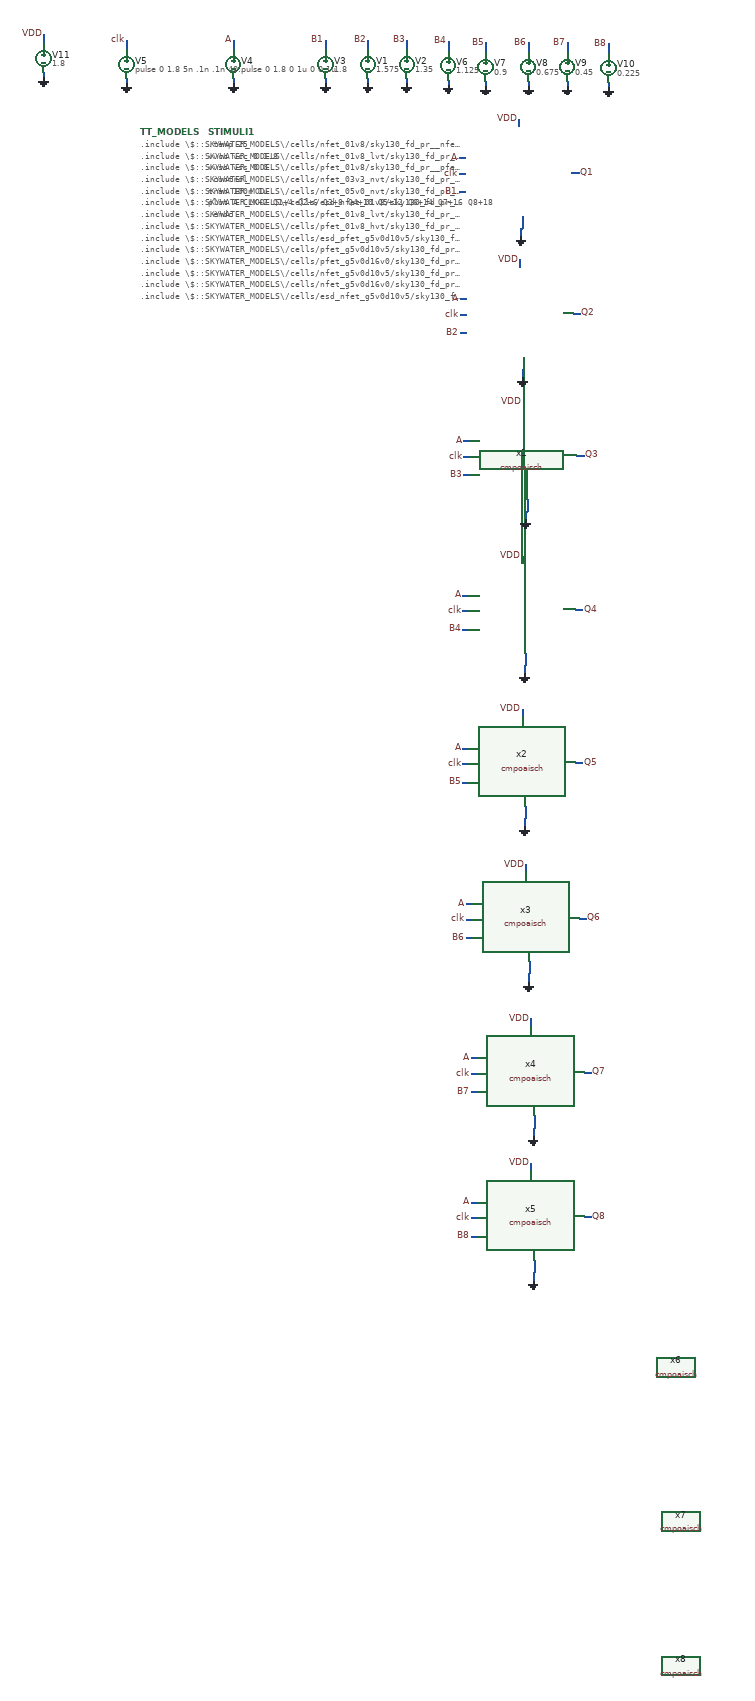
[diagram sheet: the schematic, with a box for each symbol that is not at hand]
v {xschem version=2.9.9 file_version=1.2 }
G {}
K {}
V {}
S {}
E {}
N -132.5 -1525 -132.5 -1520 { lab=GND}
N -132.5 -1542.5 -132.5 -1525 { lab=GND}
N -262.5 -1665 -250 -1665 { lab=A}
N -262.5 -1595 -250 -1595 { lab=B1}
N -132.5 -1545 -132.5 -1542.5 { lab=GND}
N -30 -1635 -15 -1635 { lab=Q1}
N -537.5 -1827.5 -537.5 -1817.5 { lab=GND}
N -727.5 -1827.5 -727.5 -1817.5 { lab=GND}
N -947.5 -1827.5 -947.5 -1817.5 { lab=GND}
N -947.5 -1907.5 -947.5 -1887.5 { lab=clk}
N -727.5 -1907.5 -727.5 -1887.5 { lab=A}
N -537.5 -1907.5 -537.5 -1887.5 { lab=B1}
N -450 -1827.5 -450 -1817.5 { lab=GND}
N -450 -1907.5 -450 -1887.5 { lab=B2}
N -370 -1827.5 -370 -1817.5 { lab=GND}
N -370 -1907.5 -370 -1887.5 { lab=B3}
N -285 -1825 -285 -1815 { lab=GND}
N -285 -1905 -285 -1885 { lab=B4}
N -207.5 -1822.5 -207.5 -1812.5 { lab=GND}
N -207.5 -1902.5 -207.5 -1882.5 { lab=B5}
N -120 -1822.5 -120 -1812.5 { lab=GND}
N -120 -1902.5 -120 -1882.5 { lab=B6}
N -40 -1822.5 -40 -1812.5 { lab=GND}
N -40 -1902.5 -40 -1882.5 { lab=B7}
N 45 -1820 45 -1810 { lab=GND}
N 45 -1900 45 -1880 { lab=B8}
N -1117.5 -1840 -1117.5 -1830 { lab=GND}
N -1117.5 -1920 -1117.5 -1900 { lab=VDD}
N -140 -1745 -140 -1730 { lab=VDD}
N -262.5 -1632.5 -250 -1632.5 { lab=clk}
N -135 -1520 -135 -1502.5 { lab=GND}
N -135 -1520 -132.5 -1520 { lab=GND}
N -130 -1235 -130 -1230 { lab=GND}
N -130 -1252.5 -130 -1235 { lab=GND}
N -260 -1375 -247.5 -1375 { lab=A}
N -260 -1305 -247.5 -1305 { lab=B2}
N -130 -1255 -130 -1252.5 { lab=GND}
N -27.5 -1345 -12.5 -1345 { lab=Q2}
N -137.5 -1455 -137.5 -1440 { lab=VDD}
N -260 -1342.5 -247.5 -1342.5 { lab=clk}
N -132.5 -1230 -132.5 -1212.5 { lab=GND}
N -132.5 -1230 -130 -1230 { lab=GND}
N -122.5 -942.5 -122.5 -937.5 { lab=GND}
N -122.5 -960 -122.5 -942.5 { lab=GND}
N -252.5 -1082.5 -240 -1082.5 { lab=A}
N -252.5 -1012.5 -240 -1012.5 { lab=B3}
N -122.5 -962.5 -122.5 -960 { lab=GND}
N -20 -1052.5 -5 -1052.5 { lab=Q3}
N -130 -1162.5 -130 -1147.5 { lab=VDD}
N -252.5 -1050 -240 -1050 { lab=clk}
N -125 -937.5 -125 -920 { lab=GND}
N -125 -937.5 -122.5 -937.5 { lab=GND}
N -125 -625 -125 -620 { lab=GND}
N -125 -642.5 -125 -625 { lab=GND}
N -255 -765 -242.5 -765 { lab=A}
N -255 -695 -242.5 -695 { lab=B4}
N -125 -645 -125 -642.5 { lab=GND}
N -22.5 -735 -7.5 -735 { lab=Q4}
N -132.5 -845 -132.5 -830 { lab=VDD}
N -255 -732.5 -242.5 -732.5 { lab=clk}
N -127.5 -620 -127.5 -602.5 { lab=GND}
N -127.5 -620 -125 -620 { lab=GND}
N -125 -310 -125 -305 { lab=GND}
N -125 -327.5 -125 -310 { lab=GND}
N -255 -450 -242.5 -450 { lab=A}
N -255 -380 -242.5 -380 { lab=B5}
N -125 -330 -125 -327.5 { lab=GND}
N -22.5 -420 -7.5 -420 { lab=Q5}
N -132.5 -530 -132.5 -515 { lab=VDD}
N -255 -417.5 -242.5 -417.5 { lab=clk}
N -127.5 -305 -127.5 -287.5 { lab=GND}
N -127.5 -305 -125 -305 { lab=GND}
N -117.5 10 -117.5 15 { lab=GND}
N -117.5 -7.5 -117.5 10 { lab=GND}
N -247.5 -130 -235 -130 { lab=A}
N -247.5 -60 -235 -60 { lab=B6}
N -117.5 -10 -117.5 -7.5 { lab=GND}
N -15 -100 0 -100 { lab=Q6}
N -125 -210 -125 -195 { lab=VDD}
N -247.5 -97.5 -235 -97.5 { lab=clk}
N -120 15 -120 32.5 { lab=GND}
N -120 15 -117.5 15 { lab=GND}
N -107.5 327.5 -107.5 332.5 { lab=GND}
N -107.5 310 -107.5 327.5 { lab=GND}
N -237.5 187.5 -225 187.5 { lab=A}
N -237.5 257.5 -225 257.5 { lab=B7}
N -107.5 307.5 -107.5 310 { lab=GND}
N -5 217.5 10 217.5 { lab=Q7}
N -115 107.5 -115 122.5 { lab=VDD}
N -237.5 220 -225 220 { lab=clk}
N -110 332.5 -110 350 { lab=GND}
N -110 332.5 -107.5 332.5 { lab=GND}
N -107.5 625 -107.5 630 { lab=GND}
N -107.5 607.5 -107.5 625 { lab=GND}
N -237.5 485 -225 485 { lab=A}
N -237.5 555 -225 555 { lab=B8}
N -107.5 605 -107.5 607.5 { lab=GND}
N -5 515 10 515 { lab=Q8}
N -115 405 -115 420 { lab=VDD}
N -237.5 517.5 -225 517.5 { lab=clk}
N -110 630 -110 647.5 { lab=GND}
N -110 630 -107.5 630 { lab=GND}
C {devices/vsource.sym} -537.5 -1857.5 0 0 {name=V3 value=1.8}
C {devices/vsource.sym} -727.5 -1857.5 0 0 {name=V4 value="pulse 0 1.8 0 1u 0 0 1u"}
C {devices/gnd.sym} -947.5 -1817.5 0 0 {name=l11 lab=GND}
C {devices/gnd.sym} -727.5 -1817.5 0 0 {name=l12 lab=GND}
C {devices/gnd.sym} -537.5 -1817.5 0 0 {name=l13 lab=GND}
C {devices/lab_pin.sym} -537.5 -1907.5 0 0 {name=l14 sig_type=std_logic lab=B1
}
C {devices/lab_pin.sym} -727.5 -1907.5 0 0 {name=l15 sig_type=std_logic lab=A
}
C {devices/lab_pin.sym} -947.5 -1907.5 0 0 {name=l16 sig_type=std_logic lab=clk}
C {devices/vsource.sym} -947.5 -1857.5 0 0 {name=V5 value="pulse 0 1.8 5n .1n .1n 40n 80n"}
C {devices/code.sym} -777.5 -1717.5 0 0 {name=STIMULI1 
only_toplevel=true
place=end
value="
.temp 25
vvcc vcc 0 1.8
vvss vss 0 0
.control
tran 100n 1u
plot A CLK+2 Q1+4 Q2+6 Q3+8 Q4+10 Q5+12 Q6+14 Q7+16 Q8+18
.endc
"}
C {devices/vsource.sym} -450 -1857.5 0 0 {name=V1 value=1.575}
C {devices/gnd.sym} -450 -1817.5 0 0 {name=l8 lab=GND}
C {devices/lab_pin.sym} -450 -1907.5 0 0 {name=l9 sig_type=std_logic lab=B2
}
C {devices/vsource.sym} -370 -1857.5 0 0 {name=V2 value=1.35}
C {devices/gnd.sym} -370 -1817.5 0 0 {name=l10 lab=GND}
C {devices/lab_pin.sym} -370 -1907.5 0 0 {name=l17 sig_type=std_logic lab=B3
}
C {devices/vsource.sym} -285 -1855 0 0 {name=V6 value=1.125}
C {devices/gnd.sym} -285 -1815 0 0 {name=l18 lab=GND}
C {devices/lab_pin.sym} -285 -1905 0 0 {name=l19 sig_type=std_logic lab=B4
}
C {devices/vsource.sym} -207.5 -1852.5 0 0 {name=V7 value=0.9}
C {devices/gnd.sym} -207.5 -1812.5 0 0 {name=l45 lab=GND}
C {devices/lab_pin.sym} -207.5 -1902.5 0 0 {name=l46 sig_type=std_logic lab=B5
}
C {devices/vsource.sym} -120 -1852.5 0 0 {name=V8 value=0.675}
C {devices/gnd.sym} -120 -1812.5 0 0 {name=l47 lab=GND}
C {devices/lab_pin.sym} -120 -1902.5 0 0 {name=l48 sig_type=std_logic lab=B6
}
C {devices/vsource.sym} -40 -1852.5 0 0 {name=V9 value=0.45}
C {devices/gnd.sym} -40 -1812.5 0 0 {name=l49 lab=GND}
C {devices/lab_pin.sym} -40 -1902.5 0 0 {name=l50 sig_type=std_logic lab=B7
}
C {devices/vsource.sym} 45 -1850 0 0 {name=V10 value=0.225}
C {devices/gnd.sym} 45 -1810 0 0 {name=l51 lab=GND}
C {devices/lab_pin.sym} 45 -1900 0 0 {name=l52 sig_type=std_logic lab=B8
}
C {devices/code.sym} -917.5 -1717.5 0 0 {name=TT_MODELS
only_toplevel=true
format="tcleval( @value )"
value="
.include \\\\$::SKYWATER_MODELS\\\\/cells/nfet_01v8/sky130_fd_pr__nfet_01v8__tt.corner.spice
.include \\\\$::SKYWATER_MODELS\\\\/cells/nfet_01v8_lvt/sky130_fd_pr__nfet_01v8_lvt__tt.corner.spice
.include \\\\$::SKYWATER_MODELS\\\\/cells/pfet_01v8/sky130_fd_pr__pfet_01v8__tt.corner.spice
.include \\\\$::SKYWATER_MODELS\\\\/cells/nfet_03v3_nvt/sky130_fd_pr__nfet_03v3_nvt__tt.corner.spice
.include \\\\$::SKYWATER_MODELS\\\\/cells/nfet_05v0_nvt/sky130_fd_pr__nfet_05v0_nvt__tt.corner.spice
.include \\\\$::SKYWATER_MODELS\\\\/cells/esd_nfet_01v8/sky130_fd_pr__esd_nfet_01v8__tt.corner.spice
.include \\\\$::SKYWATER_MODELS\\\\/cells/pfet_01v8_lvt/sky130_fd_pr__pfet_01v8_lvt__tt.corner.spice
.include \\\\$::SKYWATER_MODELS\\\\/cells/pfet_01v8_hvt/sky130_fd_pr__pfet_01v8_hvt__tt.corner.spice
.include \\\\$::SKYWATER_MODELS\\\\/cells/esd_pfet_g5v0d10v5/sky130_fd_pr__esd_pfet_g5v0d10v5__tt.corner.spice
.include \\\\$::SKYWATER_MODELS\\\\/cells/pfet_g5v0d10v5/sky130_fd_pr__pfet_g5v0d10v5__tt.corner.spice
.include \\\\$::SKYWATER_MODELS\\\\/cells/pfet_g5v0d16v0/sky130_fd_pr__pfet_g5v0d16v0__tt.corner.spice
.include \\\\$::SKYWATER_MODELS\\\\/cells/nfet_g5v0d10v5/sky130_fd_pr__nfet_g5v0d10v5__tt.corner.spice
.include \\\\$::SKYWATER_MODELS\\\\/cells/nfet_g5v0d16v0/sky130_fd_pr__nfet_g5v0d16v0__tt_discrete.corner.spice
.include \\\\$::SKYWATER_MODELS\\\\/cells/esd_nfet_g5v0d10v5/sky130_fd_pr__esd_nfet_g5v0d10v5__tt.corner.spice
.include \\\\$::SKYWATER_MODELS\\\\/models/corners/tt/nonfet.spice
* Mismatch parameters
.include \\\\$::SKYWATER_MODELS\\\\/cells/nfet_01v8/sky130_fd_pr__nfet_01v8__mismatch.corner.spice
.include \\\\$::SKYWATER_MODELS\\\\/cells/pfet_01v8/sky130_fd_pr__pfet_01v8__mismatch.corner.spice
.include \\\\$::SKYWATER_MODELS\\\\/cells/nfet_01v8_lvt/sky130_fd_pr__nfet_01v8_lvt__mismatch.corner.spice
.include \\\\$::SKYWATER_MODELS\\\\/cells/pfet_01v8_lvt/sky130_fd_pr__pfet_01v8_lvt__mismatch.corner.spice
.include \\\\$::SKYWATER_MODELS\\\\/cells/pfet_01v8_hvt/sky130_fd_pr__pfet_01v8_hvt__mismatch.corner.spice
.include \\\\$::SKYWATER_MODELS\\\\/cells/nfet_g5v0d10v5/sky130_fd_pr__nfet_g5v0d10v5__mismatch.corner.spice
.include \\\\$::SKYWATER_MODELS\\\\/cells/pfet_g5v0d10v5/sky130_fd_pr__pfet_g5v0d10v5__mismatch.corner.spice
.include \\\\$::SKYWATER_MODELS\\\\/cells/nfet_05v0_nvt/sky130_fd_pr__nfet_05v0_nvt__mismatch.corner.spice
.include \\\\$::SKYWATER_MODELS\\\\/cells/nfet_03v3_nvt/sky130_fd_pr__nfet_03v3_nvt__mismatch.corner.spice
* Resistor\\\\$::SKYWATER_MODELS\\\\/Capacitor
.include \\\\$::SKYWATER_MODELS\\\\/models/r+c/res_typical__cap_typical.spice
.include \\\\$::SKYWATER_MODELS\\\\/models/r+c/res_typical__cap_typical__lin.spice
* Special cells
.include \\\\$::SKYWATER_MODELS\\\\/models/corners/tt/specialized_cells.spice
* All models
.include \\\\$::SKYWATER_MODELS\\\\/models/all.spice
* Corner
.include \\\\$::SKYWATER_MODELS\\\\/models/corners/tt/rf.spice
.include ~/skywater-pdk/libraries/sky130_fd_sc_hd/latest/cells/nand3/sky130_fd_sc_hd__nand3_1.spice
.include ~/skywater-pdk/libraries/sky130_fd_sc_hd/latest/cells/nand2/sky130_fd_sc_hd__nand2_1.spice
.include ~/skywater-pdk/libraries/sky130_fd_sc_hd/latest/cells/nor3/sky130_fd_sc_hd__nor3_1.spice
.include ~/skywater-pdk/libraries/sky130_fd_sc_hd/latest/cells/dfrtp/sky130_fd_sc_hd__dfrtp_1.spice
.include ~/skywater-pdk/libraries/sky130_fd_sc_hd/latest/cells/nor2/sky130_fd_sc_hd__nor2_1.spice
.include ~/skywater-pdk/libraries/sky130_fd_sc_hd/latest/cells/dlrbn/sky130_fd_sc_hd__dlrbn_1.spice
.include ~/skywater-pdk/libraries/sky130_fd_sc_hd/latest/cells/a31o/sky130_fd_sc_hd__a31o_2.spice
.include ~/skywater-pdk/libraries/sky130_fd_sc_hd/latest/cells/inv/sky130_fd_sc_hd__inv_1.spice
.include ~/skywater-pdk/libraries/sky130_fd_sc_hd/latest/cells/a222oi/sky130_fd_sc_hd__a222oi_1.spice
.include ~/skywater-pdk/libraries/sky130_fd_sc_hd/latest/cells/or2/sky130_fd_sc_hd__or2_1.spice
.include ~/skywater-pdk/libraries/sky130_fd_sc_hd/latest/cells/o221ai/sky130_fd_sc_hd__o221ai_1.spice

"}
C {devices/vsource.sym} -1117.5 -1870 0 0 {name=V11 value=1.8}
C {devices/gnd.sym} -1117.5 -1830 0 0 {name=l53 lab=GND}
C {devices/lab_pin.sym} -1117.5 -1920 0 0 {name=l54 sig_type=std_logic lab=VDD
}
C {cmpoaisch.sym} 170 -710 0 0 {name=x1}
C {devices/lab_pin.sym} -262.5 -1665 0 0 {name=l1 sig_type=std_logic lab=A
}
C {devices/lab_pin.sym} -262.5 -1595 0 0 {name=l2 sig_type=std_logic lab=B1
}
C {devices/lab_pin.sym} -262.5 -1632.5 0 0 {name=l3 sig_type=std_logic lab=clk}
C {devices/lab_pin.sym} -140 -1745 0 0 {name=l4 sig_type=std_logic lab=VDD
}
C {devices/gnd.sym} -135 -1502.5 0 0 {name=l5 lab=GND}
C {devices/lab_pin.sym} -15 -1635 2 0 {name=l6 sig_type=std_logic lab=Q1
}
C {cmpoaisch.sym} 172.5 -420 0 0 {name=x2}
C {devices/lab_pin.sym} -260 -1375 0 0 {name=l7 sig_type=std_logic lab=A
}
C {devices/lab_pin.sym} -260 -1305 0 0 {name=l20 sig_type=std_logic lab=B2
}
C {devices/lab_pin.sym} -260 -1342.5 0 0 {name=l21 sig_type=std_logic lab=clk}
C {devices/lab_pin.sym} -137.5 -1455 0 0 {name=l22 sig_type=std_logic lab=VDD
}
C {devices/gnd.sym} -132.5 -1212.5 0 0 {name=l23 lab=GND}
C {devices/lab_pin.sym} -12.5 -1345 2 0 {name=l24 sig_type=std_logic lab=Q2}
C {cmpoaisch.sym} 180 -127.5 0 0 {name=x3}
C {devices/lab_pin.sym} -252.5 -1082.5 0 0 {name=l25 sig_type=std_logic lab=A
}
C {devices/lab_pin.sym} -252.5 -1012.5 0 0 {name=l26 sig_type=std_logic lab=B3
}
C {devices/lab_pin.sym} -252.5 -1050 0 0 {name=l27 sig_type=std_logic lab=clk}
C {devices/lab_pin.sym} -130 -1162.5 0 0 {name=l28 sig_type=std_logic lab=VDD
}
C {devices/gnd.sym} -125 -920 0 0 {name=l29 lab=GND}
C {devices/lab_pin.sym} -5 -1052.5 2 0 {name=l30 sig_type=std_logic lab=Q3
}
C {cmpoaisch.sym} 177.5 190 0 0 {name=x4}
C {devices/lab_pin.sym} -255 -765 0 0 {name=l31 sig_type=std_logic lab=A
}
C {devices/lab_pin.sym} -255 -695 0 0 {name=l32 sig_type=std_logic lab=B4
}
C {devices/lab_pin.sym} -255 -732.5 0 0 {name=l33 sig_type=std_logic lab=clk}
C {devices/lab_pin.sym} -132.5 -845 0 0 {name=l34 sig_type=std_logic lab=VDD
}
C {devices/gnd.sym} -127.5 -602.5 0 0 {name=l35 lab=GND}
C {devices/lab_pin.sym} -7.5 -735 2 0 {name=l36 sig_type=std_logic lab=Q4
}
C {cmpoaisch.sym} 177.5 505 0 0 {name=x5}
C {devices/lab_pin.sym} -255 -450 0 0 {name=l37 sig_type=std_logic lab=A
}
C {devices/lab_pin.sym} -255 -380 0 0 {name=l38 sig_type=std_logic lab=B5
}
C {devices/lab_pin.sym} -255 -417.5 0 0 {name=l39 sig_type=std_logic lab=clk}
C {devices/lab_pin.sym} -132.5 -530 0 0 {name=l40 sig_type=std_logic lab=VDD
}
C {devices/gnd.sym} -127.5 -287.5 0 0 {name=l41 lab=GND}
C {devices/lab_pin.sym} -7.5 -420 2 0 {name=l42 sig_type=std_logic lab=Q5
}
C {cmpoaisch.sym} 185 825 0 0 {name=x6}
C {devices/lab_pin.sym} -247.5 -130 0 0 {name=l43 sig_type=std_logic lab=A
}
C {devices/lab_pin.sym} -247.5 -60 0 0 {name=l44 sig_type=std_logic lab=B6
}
C {devices/lab_pin.sym} -247.5 -97.5 0 0 {name=l55 sig_type=std_logic lab=clk}
C {devices/lab_pin.sym} -125 -210 0 0 {name=l56 sig_type=std_logic lab=VDD
}
C {devices/gnd.sym} -120 32.5 0 0 {name=l57 lab=GND}
C {devices/lab_pin.sym} 0 -100 2 0 {name=l58 sig_type=std_logic lab=Q6
}
C {cmpoaisch.sym} 195 1142.5 0 0 {name=x7}
C {devices/lab_pin.sym} -237.5 187.5 0 0 {name=l59 sig_type=std_logic lab=A
}
C {devices/lab_pin.sym} -237.5 257.5 0 0 {name=l60 sig_type=std_logic lab=B7
}
C {devices/lab_pin.sym} -237.5 220 0 0 {name=l61 sig_type=std_logic lab=clk}
C {devices/lab_pin.sym} -115 107.5 0 0 {name=l62 sig_type=std_logic lab=VDD
}
C {devices/gnd.sym} -110 350 0 0 {name=l63 lab=GND}
C {devices/lab_pin.sym} 10 217.5 2 0 {name=l64 sig_type=std_logic lab=Q7
}
C {cmpoaisch.sym} 195 1440 0 0 {name=x8}
C {devices/lab_pin.sym} -237.5 485 0 0 {name=l65 sig_type=std_logic lab=A
}
C {devices/lab_pin.sym} -237.5 555 0 0 {name=l66 sig_type=std_logic lab=B8
}
C {devices/lab_pin.sym} -237.5 517.5 0 0 {name=l67 sig_type=std_logic lab=clk}
C {devices/lab_pin.sym} -115 405 0 0 {name=l68 sig_type=std_logic lab=VDD
}
C {devices/gnd.sym} -110 647.5 0 0 {name=l69 lab=GND}
C {devices/lab_pin.sym} 10 515 2 0 {name=l70 sig_type=std_logic lab=Q8}
